##
## LEF for PtnCells ;
## created by Innovus v19.12-s087_1 on Tue Apr 28 17:05:09 2026
##

VERSION 5.8 ;

BUSBITCHARS "[]" ;
DIVIDERCHAR "/" ;

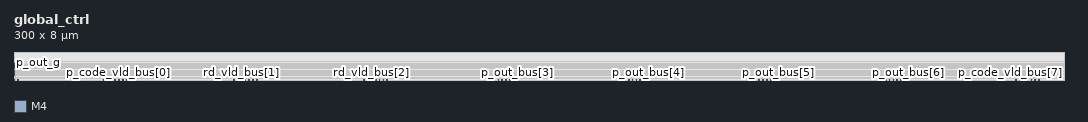
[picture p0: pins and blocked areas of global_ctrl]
MACRO global_ctrl
  CLASS BLOCK ;
  SIZE 300.000000 BY 8.000000 ;
  FOREIGN global_ctrl 0.000000 0.000000 ;
  ORIGIN 0 0 ;
  SYMMETRY X Y R90 ;
  PIN clk
    DIRECTION INPUT ;
    USE SIGNAL ;
    PORT
      LAYER M4 ;
        RECT 0.000000 0.900000 0.200000 1.100000 ;
    END
  END clk
  PIN rstn
    DIRECTION INPUT ;
    USE SIGNAL ;
    PORT
      LAYER M4 ;
        RECT 0.000000 1.400000 0.200000 1.600000 ;
    END
  END rstn
  PIN p_en
    DIRECTION INPUT ;
    USE SIGNAL ;
    PORT
      LAYER M4 ;
        RECT 0.000000 1.900000 0.200000 2.100000 ;
    END
  END p_en
  PIN en_g
    DIRECTION INPUT ;
    USE SIGNAL ;
    PORT
      LAYER M4 ;
        RECT 0.000000 2.400000 0.200000 2.600000 ;
    END
  END en_g
  PIN wr_data_in_g
    DIRECTION INPUT ;
    USE SIGNAL ;
    PORT
      LAYER M4 ;
        RECT 0.000000 2.900000 0.200000 3.100000 ;
    END
  END wr_data_in_g
  PIN rd_vld_bus[7]
    DIRECTION INPUT ;
    USE SIGNAL ;
    PORT
      LAYER M4 ;
        RECT 288.400000 0.000000 288.600000 0.200000 ;
    END
  END rd_vld_bus[7]
  PIN rd_vld_bus[6]
    DIRECTION INPUT ;
    USE SIGNAL ;
    PORT
      LAYER M4 ;
        RECT 251.150000 0.000000 251.350000 0.200000 ;
    END
  END rd_vld_bus[6]
  PIN rd_vld_bus[5]
    DIRECTION INPUT ;
    USE SIGNAL ;
    PORT
      LAYER M4 ;
        RECT 213.900000 0.000000 214.100000 0.200000 ;
    END
  END rd_vld_bus[5]
  PIN rd_vld_bus[4]
    DIRECTION INPUT ;
    USE SIGNAL ;
    PORT
      LAYER M4 ;
        RECT 176.650000 0.000000 176.850000 0.200000 ;
    END
  END rd_vld_bus[4]
  PIN rd_vld_bus[3]
    DIRECTION INPUT ;
    USE SIGNAL ;
    PORT
      LAYER M4 ;
        RECT 139.400000 0.000000 139.600000 0.200000 ;
    END
  END rd_vld_bus[3]
  PIN rd_vld_bus[2]
    DIRECTION INPUT ;
    USE SIGNAL ;
    PORT
      LAYER M4 ;
        RECT 102.150000 0.000000 102.350000 0.200000 ;
    END
  END rd_vld_bus[2]
  PIN rd_vld_bus[1]
    DIRECTION INPUT ;
    USE SIGNAL ;
    PORT
      LAYER M4 ;
        RECT 64.900000 0.000000 65.100000 0.200000 ;
    END
  END rd_vld_bus[1]
  PIN rd_vld_bus[0]
    DIRECTION INPUT ;
    USE SIGNAL ;
    PORT
      LAYER M4 ;
        RECT 27.650000 0.000000 27.850000 0.200000 ;
    END
  END rd_vld_bus[0]
  PIN rd_data_out_bus[7]
    DIRECTION INPUT ;
    USE SIGNAL ;
    PORT
      LAYER M4 ;
        RECT 289.500000 0.000000 289.700000 0.200000 ;
    END
  END rd_data_out_bus[7]
  PIN rd_data_out_bus[6]
    DIRECTION INPUT ;
    USE SIGNAL ;
    PORT
      LAYER M4 ;
        RECT 252.250000 0.000000 252.450000 0.200000 ;
    END
  END rd_data_out_bus[6]
  PIN rd_data_out_bus[5]
    DIRECTION INPUT ;
    USE SIGNAL ;
    PORT
      LAYER M4 ;
        RECT 215.000000 0.000000 215.200000 0.200000 ;
    END
  END rd_data_out_bus[5]
  PIN rd_data_out_bus[4]
    DIRECTION INPUT ;
    USE SIGNAL ;
    PORT
      LAYER M4 ;
        RECT 177.750000 0.000000 177.950000 0.200000 ;
    END
  END rd_data_out_bus[4]
  PIN rd_data_out_bus[3]
    DIRECTION INPUT ;
    USE SIGNAL ;
    PORT
      LAYER M4 ;
        RECT 140.500000 0.000000 140.700000 0.200000 ;
    END
  END rd_data_out_bus[3]
  PIN rd_data_out_bus[2]
    DIRECTION INPUT ;
    USE SIGNAL ;
    PORT
      LAYER M4 ;
        RECT 103.250000 0.000000 103.450000 0.200000 ;
    END
  END rd_data_out_bus[2]
  PIN rd_data_out_bus[1]
    DIRECTION INPUT ;
    USE SIGNAL ;
    PORT
      LAYER M4 ;
        RECT 66.000000 0.000000 66.200000 0.200000 ;
    END
  END rd_data_out_bus[1]
  PIN rd_data_out_bus[0]
    DIRECTION INPUT ;
    USE SIGNAL ;
    PORT
      LAYER M4 ;
        RECT 28.750000 0.000000 28.950000 0.200000 ;
    END
  END rd_data_out_bus[0]
  PIN p_out_vld_bus[7]
    DIRECTION INPUT ;
    USE SIGNAL ;
    PORT
      LAYER M4 ;
        RECT 291.700000 0.000000 291.900000 0.200000 ;
    END
  END p_out_vld_bus[7]
  PIN p_out_vld_bus[6]
    DIRECTION INPUT ;
    USE SIGNAL ;
    PORT
      LAYER M4 ;
        RECT 254.450000 0.000000 254.650000 0.200000 ;
    END
  END p_out_vld_bus[6]
  PIN p_out_vld_bus[5]
    DIRECTION INPUT ;
    USE SIGNAL ;
    PORT
      LAYER M4 ;
        RECT 217.200000 0.000000 217.400000 0.200000 ;
    END
  END p_out_vld_bus[5]
  PIN p_out_vld_bus[4]
    DIRECTION INPUT ;
    USE SIGNAL ;
    PORT
      LAYER M4 ;
        RECT 179.950000 0.000000 180.150000 0.200000 ;
    END
  END p_out_vld_bus[4]
  PIN p_out_vld_bus[3]
    DIRECTION INPUT ;
    USE SIGNAL ;
    PORT
      LAYER M4 ;
        RECT 142.700000 0.000000 142.900000 0.200000 ;
    END
  END p_out_vld_bus[3]
  PIN p_out_vld_bus[2]
    DIRECTION INPUT ;
    USE SIGNAL ;
    PORT
      LAYER M4 ;
        RECT 105.450000 0.000000 105.650000 0.200000 ;
    END
  END p_out_vld_bus[2]
  PIN p_out_vld_bus[1]
    DIRECTION INPUT ;
    USE SIGNAL ;
    PORT
      LAYER M4 ;
        RECT 68.200000 0.000000 68.400000 0.200000 ;
    END
  END p_out_vld_bus[1]
  PIN p_out_vld_bus[0]
    DIRECTION INPUT ;
    USE SIGNAL ;
    PORT
      LAYER M4 ;
        RECT 30.950000 0.000000 31.150000 0.200000 ;
    END
  END p_out_vld_bus[0]
  PIN p_out_bus[7]
    DIRECTION INPUT ;
    USE SIGNAL ;
    PORT
      LAYER M4 ;
        RECT 292.800000 0.000000 293.000000 0.200000 ;
    END
  END p_out_bus[7]
  PIN p_out_bus[6]
    DIRECTION INPUT ;
    USE SIGNAL ;
    PORT
      LAYER M4 ;
        RECT 255.550000 0.000000 255.750000 0.200000 ;
    END
  END p_out_bus[6]
  PIN p_out_bus[5]
    DIRECTION INPUT ;
    USE SIGNAL ;
    PORT
      LAYER M4 ;
        RECT 218.300000 0.000000 218.500000 0.200000 ;
    END
  END p_out_bus[5]
  PIN p_out_bus[4]
    DIRECTION INPUT ;
    USE SIGNAL ;
    PORT
      LAYER M4 ;
        RECT 181.050000 0.000000 181.250000 0.200000 ;
    END
  END p_out_bus[4]
  PIN p_out_bus[3]
    DIRECTION INPUT ;
    USE SIGNAL ;
    PORT
      LAYER M4 ;
        RECT 143.800000 0.000000 144.000000 0.200000 ;
    END
  END p_out_bus[3]
  PIN p_out_bus[2]
    DIRECTION INPUT ;
    USE SIGNAL ;
    PORT
      LAYER M4 ;
        RECT 106.550000 0.000000 106.750000 0.200000 ;
    END
  END p_out_bus[2]
  PIN p_out_bus[1]
    DIRECTION INPUT ;
    USE SIGNAL ;
    PORT
      LAYER M4 ;
        RECT 69.300000 0.000000 69.500000 0.200000 ;
    END
  END p_out_bus[1]
  PIN p_out_bus[0]
    DIRECTION INPUT ;
    USE SIGNAL ;
    PORT
      LAYER M4 ;
        RECT 32.050000 0.000000 32.250000 0.200000 ;
    END
  END p_out_bus[0]
  PIN couple_en
    DIRECTION OUTPUT ;
    USE SIGNAL ;
    PORT
      LAYER M4 ;
        RECT 0.000000 0.000000 0.200000 0.200000 ;
    END
  END couple_en
  PIN wr_data_in_g_d2
    DIRECTION OUTPUT ;
    USE SIGNAL ;
    PORT
      LAYER M4 ;
        RECT 1.100000 0.000000 1.300000 0.200000 ;
    END
  END wr_data_in_g_d2
  PIN rd_vld_g
    DIRECTION OUTPUT ;
    USE SIGNAL ;
    PORT
      LAYER M4 ;
        RECT 0.000000 3.400000 0.200000 3.600000 ;
    END
  END rd_vld_g
  PIN rd_data_out_g
    DIRECTION OUTPUT ;
    USE SIGNAL ;
    PORT
      LAYER M4 ;
        RECT 0.000000 3.900000 0.200000 4.100000 ;
    END
  END rd_data_out_g
  PIN wr_vld_bus[7]
    DIRECTION OUTPUT ;
    USE SIGNAL ;
    PORT
      LAYER M4 ;
        RECT 286.200000 0.000000 286.400000 0.200000 ;
    END
  END wr_vld_bus[7]
  PIN wr_vld_bus[6]
    DIRECTION OUTPUT ;
    USE SIGNAL ;
    PORT
      LAYER M4 ;
        RECT 248.950000 0.000000 249.150000 0.200000 ;
    END
  END wr_vld_bus[6]
  PIN wr_vld_bus[5]
    DIRECTION OUTPUT ;
    USE SIGNAL ;
    PORT
      LAYER M4 ;
        RECT 211.700000 0.000000 211.900000 0.200000 ;
    END
  END wr_vld_bus[5]
  PIN wr_vld_bus[4]
    DIRECTION OUTPUT ;
    USE SIGNAL ;
    PORT
      LAYER M4 ;
        RECT 174.450000 0.000000 174.650000 0.200000 ;
    END
  END wr_vld_bus[4]
  PIN wr_vld_bus[3]
    DIRECTION OUTPUT ;
    USE SIGNAL ;
    PORT
      LAYER M4 ;
        RECT 137.200000 0.000000 137.400000 0.200000 ;
    END
  END wr_vld_bus[3]
  PIN wr_vld_bus[2]
    DIRECTION OUTPUT ;
    USE SIGNAL ;
    PORT
      LAYER M4 ;
        RECT 99.950000 0.000000 100.150000 0.200000 ;
    END
  END wr_vld_bus[2]
  PIN wr_vld_bus[1]
    DIRECTION OUTPUT ;
    USE SIGNAL ;
    PORT
      LAYER M4 ;
        RECT 62.700000 0.000000 62.900000 0.200000 ;
    END
  END wr_vld_bus[1]
  PIN wr_vld_bus[0]
    DIRECTION OUTPUT ;
    USE SIGNAL ;
    PORT
      LAYER M4 ;
        RECT 25.450000 0.000000 25.650000 0.200000 ;
    END
  END wr_vld_bus[0]
  PIN rd_rdy_bus[7]
    DIRECTION OUTPUT ;
    USE SIGNAL ;
    PORT
      LAYER M4 ;
        RECT 287.300000 0.000000 287.500000 0.200000 ;
    END
  END rd_rdy_bus[7]
  PIN rd_rdy_bus[6]
    DIRECTION OUTPUT ;
    USE SIGNAL ;
    PORT
      LAYER M4 ;
        RECT 250.050000 0.000000 250.250000 0.200000 ;
    END
  END rd_rdy_bus[6]
  PIN rd_rdy_bus[5]
    DIRECTION OUTPUT ;
    USE SIGNAL ;
    PORT
      LAYER M4 ;
        RECT 212.800000 0.000000 213.000000 0.200000 ;
    END
  END rd_rdy_bus[5]
  PIN rd_rdy_bus[4]
    DIRECTION OUTPUT ;
    USE SIGNAL ;
    PORT
      LAYER M4 ;
        RECT 175.550000 0.000000 175.750000 0.200000 ;
    END
  END rd_rdy_bus[4]
  PIN rd_rdy_bus[3]
    DIRECTION OUTPUT ;
    USE SIGNAL ;
    PORT
      LAYER M4 ;
        RECT 138.300000 0.000000 138.500000 0.200000 ;
    END
  END rd_rdy_bus[3]
  PIN rd_rdy_bus[2]
    DIRECTION OUTPUT ;
    USE SIGNAL ;
    PORT
      LAYER M4 ;
        RECT 101.050000 0.000000 101.250000 0.200000 ;
    END
  END rd_rdy_bus[2]
  PIN rd_rdy_bus[1]
    DIRECTION OUTPUT ;
    USE SIGNAL ;
    PORT
      LAYER M4 ;
        RECT 63.800000 0.000000 64.000000 0.200000 ;
    END
  END rd_rdy_bus[1]
  PIN rd_rdy_bus[0]
    DIRECTION OUTPUT ;
    USE SIGNAL ;
    PORT
      LAYER M4 ;
        RECT 26.550000 0.000000 26.750000 0.200000 ;
    END
  END rd_rdy_bus[0]
  PIN p_code_vld_bus[7]
    DIRECTION OUTPUT ;
    USE SIGNAL ;
    PORT
      LAYER M4 ;
        RECT 290.600000 0.000000 290.800000 0.200000 ;
    END
  END p_code_vld_bus[7]
  PIN p_code_vld_bus[6]
    DIRECTION OUTPUT ;
    USE SIGNAL ;
    PORT
      LAYER M4 ;
        RECT 253.350000 0.000000 253.550000 0.200000 ;
    END
  END p_code_vld_bus[6]
  PIN p_code_vld_bus[5]
    DIRECTION OUTPUT ;
    USE SIGNAL ;
    PORT
      LAYER M4 ;
        RECT 216.100000 0.000000 216.300000 0.200000 ;
    END
  END p_code_vld_bus[5]
  PIN p_code_vld_bus[4]
    DIRECTION OUTPUT ;
    USE SIGNAL ;
    PORT
      LAYER M4 ;
        RECT 178.850000 0.000000 179.050000 0.200000 ;
    END
  END p_code_vld_bus[4]
  PIN p_code_vld_bus[3]
    DIRECTION OUTPUT ;
    USE SIGNAL ;
    PORT
      LAYER M4 ;
        RECT 141.600000 0.000000 141.800000 0.200000 ;
    END
  END p_code_vld_bus[3]
  PIN p_code_vld_bus[2]
    DIRECTION OUTPUT ;
    USE SIGNAL ;
    PORT
      LAYER M4 ;
        RECT 104.350000 0.000000 104.550000 0.200000 ;
    END
  END p_code_vld_bus[2]
  PIN p_code_vld_bus[1]
    DIRECTION OUTPUT ;
    USE SIGNAL ;
    PORT
      LAYER M4 ;
        RECT 67.100000 0.000000 67.300000 0.200000 ;
    END
  END p_code_vld_bus[1]
  PIN p_code_vld_bus[0]
    DIRECTION OUTPUT ;
    USE SIGNAL ;
    PORT
      LAYER M4 ;
        RECT 29.850000 0.000000 30.050000 0.200000 ;
    END
  END p_code_vld_bus[0]
  PIN p_out_vld_g
    DIRECTION OUTPUT ;
    USE SIGNAL ;
    PORT
      LAYER M4 ;
        RECT 0.000000 4.400000 0.200000 4.600000 ;
    END
  END p_out_vld_g
  PIN p_out_g
    DIRECTION OUTPUT ;
    USE SIGNAL ;
    PORT
      LAYER M4 ;
        RECT 0.000000 4.900000 0.200000 5.100000 ;
    END
  END p_out_g
  OBS
    LAYER M1 ;
      RECT 0.000000 0.000000 300.000000 8.000000 ;
    LAYER M2 ;
      RECT 0.000000 0.000000 300.000000 8.000000 ;
    LAYER M3 ;
      RECT 0.000000 0.000000 300.000000 8.000000 ;
    LAYER M4 ;
      RECT 0.000000 5.200000 300.000000 8.000000 ;
      RECT 0.300000 4.800000 300.000000 5.200000 ;
      RECT 0.000000 4.700000 300.000000 4.800000 ;
      RECT 0.300000 4.300000 300.000000 4.700000 ;
      RECT 0.000000 4.200000 300.000000 4.300000 ;
      RECT 0.300000 3.800000 300.000000 4.200000 ;
      RECT 0.000000 3.700000 300.000000 3.800000 ;
      RECT 0.300000 3.300000 300.000000 3.700000 ;
      RECT 0.000000 3.200000 300.000000 3.300000 ;
      RECT 0.300000 2.800000 300.000000 3.200000 ;
      RECT 0.000000 2.700000 300.000000 2.800000 ;
      RECT 0.300000 2.300000 300.000000 2.700000 ;
      RECT 0.000000 2.200000 300.000000 2.300000 ;
      RECT 0.300000 1.800000 300.000000 2.200000 ;
      RECT 0.000000 1.700000 300.000000 1.800000 ;
      RECT 0.300000 1.300000 300.000000 1.700000 ;
      RECT 0.000000 1.200000 300.000000 1.300000 ;
      RECT 0.300000 0.800000 300.000000 1.200000 ;
      RECT 0.000000 0.300000 300.000000 0.800000 ;
      RECT 293.100000 0.000000 300.000000 0.300000 ;
      RECT 292.000000 0.000000 292.700000 0.300000 ;
      RECT 290.900000 0.000000 291.600000 0.300000 ;
      RECT 289.800000 0.000000 290.500000 0.300000 ;
      RECT 288.700000 0.000000 289.400000 0.300000 ;
      RECT 287.600000 0.000000 288.300000 0.300000 ;
      RECT 286.500000 0.000000 287.200000 0.300000 ;
      RECT 255.850000 0.000000 286.100000 0.300000 ;
      RECT 254.750000 0.000000 255.450000 0.300000 ;
      RECT 253.650000 0.000000 254.350000 0.300000 ;
      RECT 252.550000 0.000000 253.250000 0.300000 ;
      RECT 251.450000 0.000000 252.150000 0.300000 ;
      RECT 250.350000 0.000000 251.050000 0.300000 ;
      RECT 249.250000 0.000000 249.950000 0.300000 ;
      RECT 218.600000 0.000000 248.850000 0.300000 ;
      RECT 217.500000 0.000000 218.200000 0.300000 ;
      RECT 216.400000 0.000000 217.100000 0.300000 ;
      RECT 215.300000 0.000000 216.000000 0.300000 ;
      RECT 214.200000 0.000000 214.900000 0.300000 ;
      RECT 213.100000 0.000000 213.800000 0.300000 ;
      RECT 212.000000 0.000000 212.700000 0.300000 ;
      RECT 181.350000 0.000000 211.600000 0.300000 ;
      RECT 180.250000 0.000000 180.950000 0.300000 ;
      RECT 179.150000 0.000000 179.850000 0.300000 ;
      RECT 178.050000 0.000000 178.750000 0.300000 ;
      RECT 176.950000 0.000000 177.650000 0.300000 ;
      RECT 175.850000 0.000000 176.550000 0.300000 ;
      RECT 174.750000 0.000000 175.450000 0.300000 ;
      RECT 144.100000 0.000000 174.350000 0.300000 ;
      RECT 143.000000 0.000000 143.700000 0.300000 ;
      RECT 141.900000 0.000000 142.600000 0.300000 ;
      RECT 140.800000 0.000000 141.500000 0.300000 ;
      RECT 139.700000 0.000000 140.400000 0.300000 ;
      RECT 138.600000 0.000000 139.300000 0.300000 ;
      RECT 137.500000 0.000000 138.200000 0.300000 ;
      RECT 106.850000 0.000000 137.100000 0.300000 ;
      RECT 105.750000 0.000000 106.450000 0.300000 ;
      RECT 104.650000 0.000000 105.350000 0.300000 ;
      RECT 103.550000 0.000000 104.250000 0.300000 ;
      RECT 102.450000 0.000000 103.150000 0.300000 ;
      RECT 101.350000 0.000000 102.050000 0.300000 ;
      RECT 100.250000 0.000000 100.950000 0.300000 ;
      RECT 69.600000 0.000000 99.850000 0.300000 ;
      RECT 68.500000 0.000000 69.200000 0.300000 ;
      RECT 67.400000 0.000000 68.100000 0.300000 ;
      RECT 66.300000 0.000000 67.000000 0.300000 ;
      RECT 65.200000 0.000000 65.900000 0.300000 ;
      RECT 64.100000 0.000000 64.800000 0.300000 ;
      RECT 63.000000 0.000000 63.700000 0.300000 ;
      RECT 32.350000 0.000000 62.600000 0.300000 ;
      RECT 31.250000 0.000000 31.950000 0.300000 ;
      RECT 30.150000 0.000000 30.850000 0.300000 ;
      RECT 29.050000 0.000000 29.750000 0.300000 ;
      RECT 27.950000 0.000000 28.650000 0.300000 ;
      RECT 26.850000 0.000000 27.550000 0.300000 ;
      RECT 25.750000 0.000000 26.450000 0.300000 ;
      RECT 1.400000 0.000000 25.350000 0.300000 ;
      RECT 0.300000 0.000000 1.000000 0.300000 ;
  END
END global_ctrl

END LIBRARY
